VERSION 5.7 ;
  NOWIREEXTENSIONATPIN ON ;
  DIVIDERCHAR "/" ;
  BUSBITCHARS "[]" ;
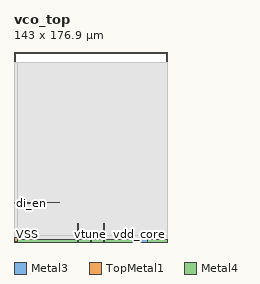
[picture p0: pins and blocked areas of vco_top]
MACRO vco_top
  CLASS BLOCK ;
  FOREIGN vco_top ;
  ORIGIN 0.000 0.000 ;
  SIZE 143.000 BY 176.900 ;
  PIN di_en
    ANTENNAGATEAREA 0.195000 ;
    PORT
      LAYER Metal3 ;
        RECT 0.000 35.990 30.350 36.290 ;
    END
  END di_en
  PIN ibias_100u
    ANTENNAGATEAREA 2.500000 ;
    ANTENNADIFFAREA 1.190000 ;
    PORT
      LAYER Metal3 ;
        RECT 0.000 36.500 42.645 36.800 ;
    END
  END ibias_100u
  PIN vtune
    ANTENNADIFFAREA 59.040897 ;
    PORT
      LAYER Metal3 ;
        RECT 71.200 0.000 71.800 2.295 ;
    END
  END vtune
  PIN rf_out_p
    ANTENNADIFFAREA 4.560000 ;
    PORT
      LAYER Metal3 ;
        RECT 83.200 0.000 83.800 17.235 ;
    END
  END rf_out_p
  PIN rf_out_n
    ANTENNADIFFAREA 4.560000 ;
    PORT
      LAYER Metal3 ;
        RECT 59.200 0.000 59.800 17.235 ;
    END
  END rf_out_n
  PIN vdd_core
    ANTENNAGATEAREA 5.200000 ;
    ANTENNADIFFAREA 7.600000 ;
    PORT
      LAYER Metal3 ;
        RECT 116.500 0.000 124.500 7.200 ;
    END
  END vdd_core
  PIN VSS
    USE GROUND ;
    PORT
      LAYER TopMetal1 ;
        RECT 0.000 0.500 3.270 4.500 ;
    END
  END VSS
  PIN VDD
    USE POWER ;
    PORT
      LAYER Metal4 ;
        RECT 0.000 0.000 143.000 2.000 ;
    END
  END VDD
  OBS
      LAYER GatPoly ;
        RECT 5.370 7.900 96.000 80.400 ;
      LAYER Metal1 ;
        RECT 0.500 6.870 141.000 80.370 ;
      LAYER Metal2 ;
        RECT 0.735 6.965 141.000 78.900 ;
      LAYER Metal3 ;
        RECT 0.735 37.010 141.000 166.900 ;
        RECT 42.855 36.290 141.000 37.010 ;
        RECT 30.560 35.780 141.000 36.290 ;
        RECT 0.735 17.445 141.000 35.780 ;
        RECT 0.735 2.295 58.990 17.445 ;
        RECT 60.010 2.505 82.990 17.445 ;
        RECT 60.010 2.295 70.990 2.505 ;
        RECT 72.010 2.295 82.990 2.505 ;
        RECT 84.010 7.410 141.000 17.445 ;
        RECT 84.010 2.295 116.290 7.410 ;
        RECT 124.710 2.295 141.000 7.410 ;
      LAYER Metal4 ;
        RECT 0.600 2.210 142.300 166.900 ;
      LAYER TopMetal1 ;
        RECT 2.950 6.140 143.000 166.900 ;
        RECT 4.910 0.500 143.000 6.140 ;
  END
END vco_top
END LIBRARY

